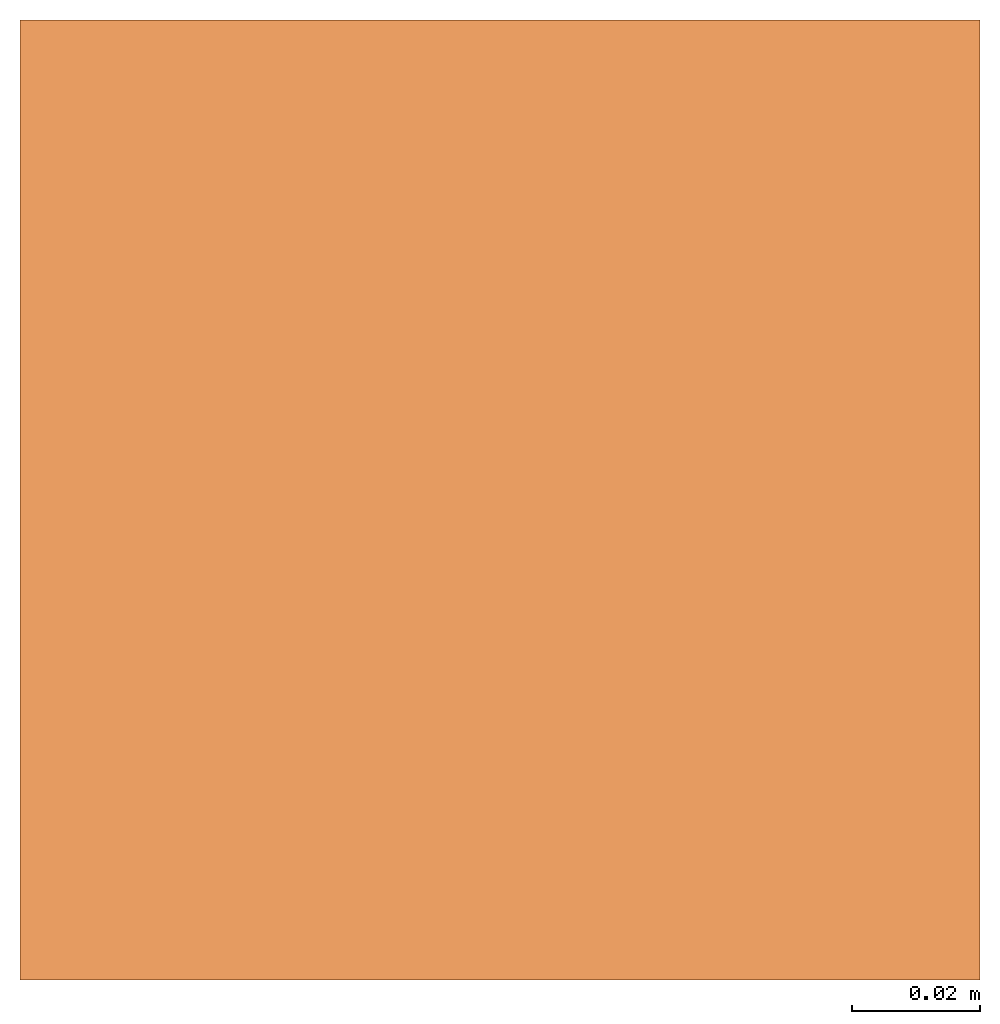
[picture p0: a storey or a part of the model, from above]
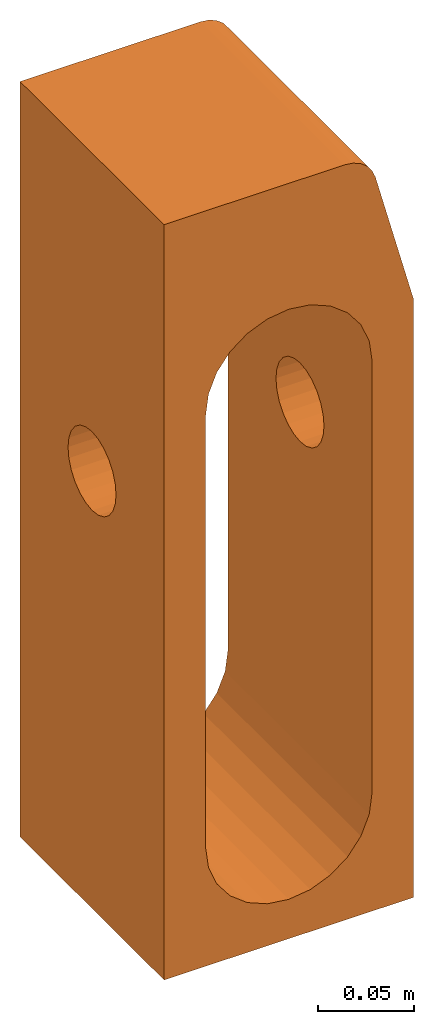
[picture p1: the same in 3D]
Properties of the parts of a building model (IFC2X3)

# File
Description: ViewDefinition [CoordinationView]
File name: 4943 - Cable Loop - 150mm LG.ifc
Time: 2013-09-18T16:26:30
Written by: Autodesk Revit 2013
Made in: 20120221_2030(x64)

# IfcProject, Project Number
LongName: Project Name; Phase: Project Status

# IfcSite, Default
RefLatitude: 42, 21, 30, 344238; RefLongitude: -71, -3, -35, -194702; RefElevation: 0 mm

# IfcBuilding
Pset_BuildingCommon - NumberOfStoreys: 2
Other - Project Issue Date: Issue Date; Client Name: Owner; Project Number: Project Number; Project Status: Project Status; Project Name: Project Name; Project Address: Enter address here

# IfcBuildingStorey (2)
Constraints - Elevation Base: 0
Graphics - Line Weight: 1; Line Pattern: Center; Symbol at End 2 Default: yes; Symbol at End 1 Default: no; Color: 0; Symbol: M_Level Head - Circle: M_Level Head - Circle
Identity Data - Building Story: yes; Structural: no
Dimensions - Computation Height: 0 mm
Name | LongName = Name | Elevation (mm) = Constraints, Elevation (mm)
T.O. Fnd. Wall | T.O. Fnd. Wall | -300
Level 1 | Level 1 | 0

# IfcBuildingElementProxy: 4943 - Cable Loop - 150mm LG, Civil-Drainage-Channel-ACO-KerbDrain-HB480(amar):4943 - Cable Loop - 150mm LG:4943 - Cable Loop - 150mm LG:481515
In: T.O. Fnd. Wall
Material: ACO Polymer Concrete.
General - TagNumber: 0.000000; SerialNumber: 0.000000
Dimensions - Void Depth: -355 mm; Void Start I/O: 0 mm; Mitre Long end: 500 mm; junction void depth: 2000 mm; Void Length: 150 mm; Junction End: 2 mm; Junction Start: 0 mm; Void End I/O: 2 mm; I/O endcap void depth: 2000 mm; Mitre Void Start: -8787 mm; Mitre Void End: -8790 mm; Mitre Small End: 487 mm; Void Width: 150 mm; Straight Void Start: 0 mm; Volume: 5191712 mm3
Constraints - Moves With Nearby Elements: no; Level: Level: Level 1
Phasing - Phase Created: Phase 1
Pset_BuildingElementProxyCommon - Reference: 4943 - Cable Loop - 150mm LG
Other - Revision: 1; CreatedBy: www.aco.co.uk
Identity Data - Telephone: +44 (0)1462 816666; Model: ACO KerbDrain HB480; e-mail Technical: technical@aco.co.uk; Product brochure: http://www.aco.co.uk/download.php?id=120; Price: POA - contact ACO; Fax: +44 (0)1462 815895; Type Comments: ACO KerbDrain HB480 half battered cable loop unit 150mm long; Installation guidelines: http://www.aco.co.uk/download.php?id=120; Manufacturer: ACO Technologies plc - ACO Water Management Division; Assembly Code: D2040; OmniClass Number: 23.70.50.24; Product Page URL: http://www.aco.co.uk/product_detail.php?id=3; Model Description: Combined kerb and drainage system; URL: www.aco.co.uk; Maintenance guidelines: http://www.aco.co.uk/download.php?id=120; Assembly Description: Rain Water Drainage; e-mail Sales: customersupport@aco.co.uk; Cost: 0; Address: ACO Business Park, Hitchin Road, Shefford, Bedfordshire, United Kingdom SG17 5TE; OmniClass Title: Rainwater Removal; Product Code: 4943
Data - Concrete Surround Volume - Load Class A 15 - D 400 - Grass or Asphalt Pavement: N/A; Product Dimensions: 150mm x 150mm x 480mm (LxWxH); Invert Depth: 455mm; Product Standard: BS EN 1433:2002, CE marked, Kitemarked; Connection Pipe O.D: N/A; Drainage Slot Width: N/A; Installation - Concrete Grade: Refer to brochure; ACO Hydraulic Design Software: http://www.acodesign.co.uk; Load Class: A 15 - D 400; Drainage Slot Intake area: N/A; Channel C.S.A: 0.04mm²; Concrete Surround Volume - Load Class A 15 - D 400 - Concrete Pavement: N/A; Product Weight: 12.2 Kg; Hydraulic Performance: http://www.aco.co.uk/download.php?id=120
Materials and Finishes - Channel Material: Vienite® Synthetic Resin Concrete; End Cap Colour: N/A; Connection Pipe Material: N/A; Access Cover/Frame Material: N/A; End Cap Material: N/A; Connection Pipe Material Colour: N/A; Access Cover/Frame Colour: N/A; Access Cover/Frame Finish: N/A; Channel Colour: Grey
Green Building Properties - Channel Recycled Material Content: 20% minimum; End Cap Recyclable: N/A; Access Cover/Frame Recycled Material Content: N/A; End Cap Recycled Material Content: N/A; Access Cover/Frame Recyclable: N/A; Channel Recyclable: Fully recyclable
Construction - RH inlet/outlet end cap: no; Junction channel: no; perforated centre stone: no; KDHB480 500_blindunit: no; Junction access unit: no; 25-11m internal mitre: no; HB480-500: no; Centre Stone: no; Access Unit: no; LH inlet/outlet end cap: no; LH drop kerb: no; Closing end cap: no; RH BS transition kerb: no; 10-8m external mitre: no; cable loop: yes; LH BS transition kerb: no; Bus stop kerb: no; 25-11m external mitre: no; Junction end cap: no; 7-6m external mitre: no; RH drop kerb: no

# IfcOpeningElement: Opening (3)
In: Level 1
Structural - Enable Analytical Model: no; Structural: no
Dimensions - Volume: 2352712500 mm3; Thickness: 400 mm; Perimeter: 9790 mm; Area: 5901750 mm2
Constraints - Related to Mass: no; Room Bounding: yes; Height Offset From Level: 0 mm; Level: Level: Level 1
Phasing - Phase Created: Phase 1
Construction - Function: 0; Default Thickness: 400 mm
Analytical Properties - Thermal Resistance (R): 0.477897; Roughness: 1; Thermal mass: 543920; Heat Transfer Coefficient (U): 2.0925; Absorptance: 0.1
Materials and Finishes - Structural Material: Earth
Graphics - Coarse Scale Fill Color: 0

# IfcSlab: Floor:Generic Floor - 400mm, Floor:Generic Floor - 400mm:136426
In: Level 1
PredefinedType: FLOOR; Material: Earth 400 mm
Structural - Enable Analytical Model: no; Structural: no
Dimensions - Volume: 2352712500 mm3; Thickness: 400 mm; Perimeter: 9790 mm; Area: 5901750 mm2
Constraints - Related to Mass: no; Room Bounding: yes; Height Offset From Level: 0 mm; Level: Level: Level 1
Phasing - Phase Created: Phase 1
Pset_SlabCommon - Reference: Generic Floor - 400mm; IsExternal: no; LoadBearing: yes
Construction - Function: 0; Default Thickness: 400 mm
Analytical Properties - Thermal Resistance (R): 0.477897; Roughness: 1; Thermal mass: 543920; Heat Transfer Coefficient (U): 2.0925; Absorptance: 0.1
Materials and Finishes - Structural Material: Earth
Graphics - Coarse Scale Fill Color: 0
